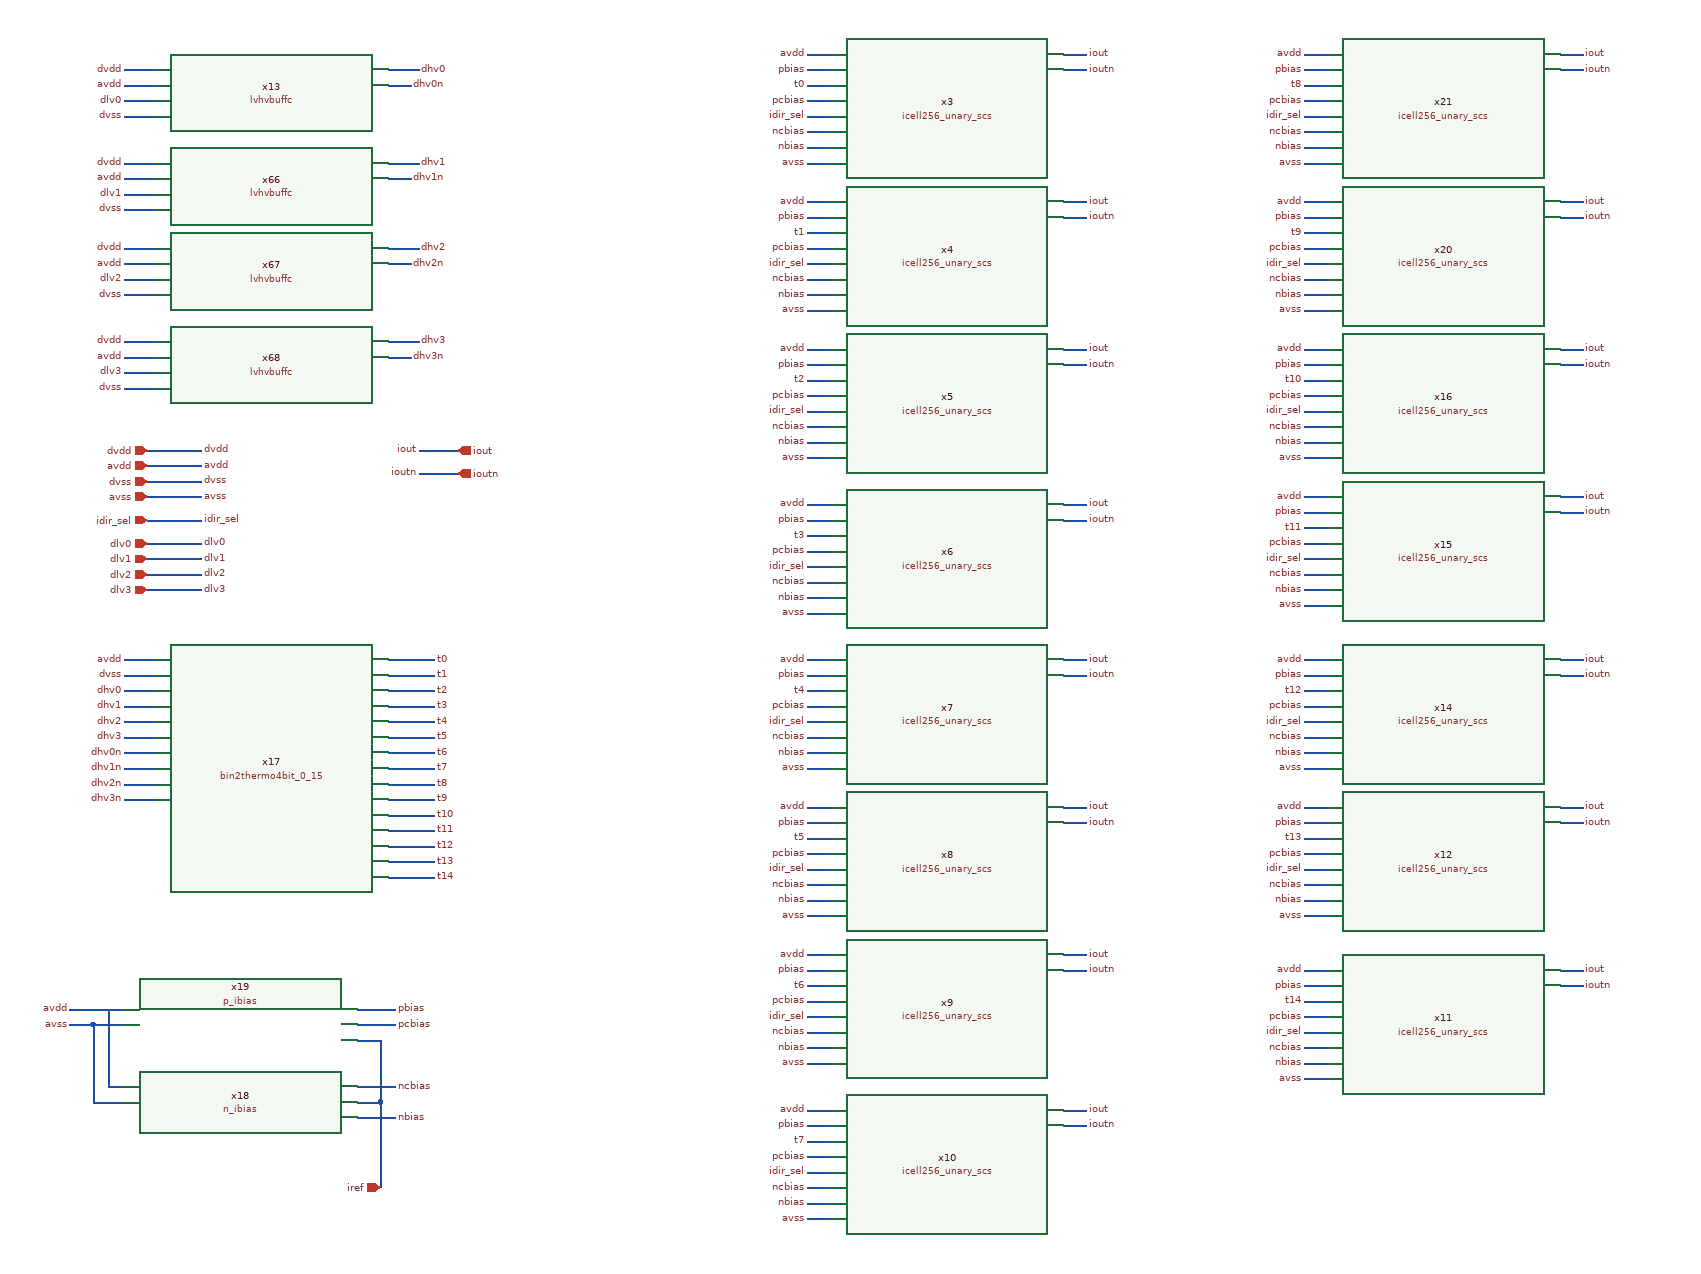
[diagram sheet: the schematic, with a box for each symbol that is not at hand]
v {xschem version=3.4.5 file_version=1.2
}
G {}
K {}
V {}
S {}
E {}
N -50 150 -20 150 {
lab=avss}
N -50 130 -20 130 {
lab=nbias}
N -50 110 -20 110 {
lab=ncbias}
N -50 90 -20 90 {
lab=idir_sel}
N -50 70 -20 70 {
lab=pcbias}
N -50 50 -20 50 {
lab=t0}
N -50 30 -20 30 {
lab=pbias}
N -50 10 -20 10 {
lab=avdd}
N 280 10 310 10 {
lab=iout}
N 280 30 310 30 {
lab=ioutn}
N -50 340 -20 340 {
lab=avss}
N -50 320 -20 320 {
lab=nbias}
N -50 300 -20 300 {
lab=ncbias}
N -50 280 -20 280 {
lab=idir_sel}
N -50 260 -20 260 {
lab=pcbias}
N -50 240 -20 240 {
lab=t1}
N -50 220 -20 220 {
lab=pbias}
N -50 200 -20 200 {
lab=avdd}
N 280 200 310 200 {
lab=iout}
N 280 220 310 220 {
lab=ioutn}
N -50 530 -20 530 {
lab=avss}
N -50 510 -20 510 {
lab=nbias}
N -50 490 -20 490 {
lab=ncbias}
N -50 470 -20 470 {
lab=idir_sel}
N -50 450 -20 450 {
lab=pcbias}
N -50 430 -20 430 {
lab=t2}
N -50 410 -20 410 {
lab=pbias}
N -50 390 -20 390 {
lab=avdd}
N 280 390 310 390 {
lab=iout}
N 280 410 310 410 {
lab=ioutn}
N -50 730 -20 730 {
lab=avss}
N -50 710 -20 710 {
lab=nbias}
N -50 690 -20 690 {
lab=ncbias}
N -50 670 -20 670 {
lab=idir_sel}
N -50 650 -20 650 {
lab=pcbias}
N -50 630 -20 630 {
lab=t3}
N -50 610 -20 610 {
lab=pbias}
N -50 590 -20 590 {
lab=avdd}
N 280 590 310 590 {
lab=iout}
N 280 610 310 610 {
lab=ioutn}
N -50 930 -20 930 {
lab=avss}
N -50 910 -20 910 {
lab=nbias}
N -50 890 -20 890 {
lab=ncbias}
N -50 870 -20 870 {
lab=idir_sel}
N -50 850 -20 850 {
lab=pcbias}
N -50 830 -20 830 {
lab=t4}
N -50 810 -20 810 {
lab=pbias}
N -50 790 -20 790 {
lab=avdd}
N 280 790 310 790 {
lab=iout}
N 280 810 310 810 {
lab=ioutn}
N -50 1120 -20 1120 {
lab=avss}
N -50 1100 -20 1100 {
lab=nbias}
N -50 1080 -20 1080 {
lab=ncbias}
N -50 1060 -20 1060 {
lab=idir_sel}
N -50 1040 -20 1040 {
lab=pcbias}
N -50 1020 -20 1020 {
lab=t5}
N -50 1000 -20 1000 {
lab=pbias}
N -50 980 -20 980 {
lab=avdd}
N 280 980 310 980 {
lab=iout}
N 280 1000 310 1000 {
lab=ioutn}
N -50 1310 -20 1310 {
lab=avss}
N -50 1290 -20 1290 {
lab=nbias}
N -50 1270 -20 1270 {
lab=ncbias}
N -50 1250 -20 1250 {
lab=idir_sel}
N -50 1230 -20 1230 {
lab=pcbias}
N -50 1210 -20 1210 {
lab=t6}
N -50 1190 -20 1190 {
lab=pbias}
N -50 1170 -20 1170 {
lab=avdd}
N 280 1170 310 1170 {
lab=iout}
N 280 1190 310 1190 {
lab=ioutn}
N -50 1510 -20 1510 {
lab=avss}
N -50 1490 -20 1490 {
lab=nbias}
N -50 1470 -20 1470 {
lab=ncbias}
N -50 1450 -20 1450 {
lab=idir_sel}
N -50 1430 -20 1430 {
lab=pcbias}
N -50 1410 -20 1410 {
lab=t7}
N -50 1390 -20 1390 {
lab=pbias}
N -50 1370 -20 1370 {
lab=avdd}
N 280 1370 310 1370 {
lab=iout}
N 280 1390 310 1390 {
lab=ioutn}
N 590 1330 620 1330 {
lab=avss}
N 590 1310 620 1310 {
lab=nbias}
N 590 1290 620 1290 {
lab=ncbias}
N 590 1270 620 1270 {
lab=idir_sel}
N 590 1250 620 1250 {
lab=pcbias}
N 590 1230 620 1230 {
lab=t14}
N 590 1210 620 1210 {
lab=pbias}
N 590 1190 620 1190 {
lab=avdd}
N 920 1190 950 1190 {
lab=iout}
N 920 1210 950 1210 {
lab=ioutn}
N 590 1120 620 1120 {
lab=avss}
N 590 1100 620 1100 {
lab=nbias}
N 590 1080 620 1080 {
lab=ncbias}
N 590 1060 620 1060 {
lab=idir_sel}
N 590 1040 620 1040 {
lab=pcbias}
N 590 1020 620 1020 {
lab=t13}
N 590 1000 620 1000 {
lab=pbias}
N 590 980 620 980 {
lab=avdd}
N 920 980 950 980 {
lab=iout}
N 920 1000 950 1000 {
lab=ioutn}
N 590 930 620 930 {
lab=avss}
N 590 910 620 910 {
lab=nbias}
N 590 890 620 890 {
lab=ncbias}
N 590 870 620 870 {
lab=idir_sel}
N 590 850 620 850 {
lab=pcbias}
N 590 830 620 830 {
lab=t12}
N 590 810 620 810 {
lab=pbias}
N 590 790 620 790 {
lab=avdd}
N 920 790 950 790 {
lab=iout}
N 920 810 950 810 {
lab=ioutn}
N 590 720 620 720 {
lab=avss}
N 590 700 620 700 {
lab=nbias}
N 590 680 620 680 {
lab=ncbias}
N 590 660 620 660 {
lab=idir_sel}
N 590 640 620 640 {
lab=pcbias}
N 590 620 620 620 {
lab=t11}
N 590 600 620 600 {
lab=pbias}
N 590 580 620 580 {
lab=avdd}
N 920 580 950 580 {
lab=iout}
N 920 600 950 600 {
lab=ioutn}
N 590 530 620 530 {
lab=avss}
N 590 510 620 510 {
lab=nbias}
N 590 490 620 490 {
lab=ncbias}
N 590 470 620 470 {
lab=idir_sel}
N 590 450 620 450 {
lab=pcbias}
N 590 430 620 430 {
lab=t10}
N 590 410 620 410 {
lab=pbias}
N 590 390 620 390 {
lab=avdd}
N 920 390 950 390 {
lab=iout}
N 920 410 950 410 {
lab=ioutn}
N 590 340 620 340 {
lab=avss}
N 590 320 620 320 {
lab=nbias}
N 590 300 620 300 {
lab=ncbias}
N 590 280 620 280 {
lab=idir_sel}
N 590 260 620 260 {
lab=pcbias}
N 590 240 620 240 {
lab=t9}
N 590 220 620 220 {
lab=pbias}
N 590 200 620 200 {
lab=avdd}
N 920 200 950 200 {
lab=iout}
N 920 220 950 220 {
lab=ioutn}
N 590 150 620 150 {
lab=avss}
N 590 130 620 130 {
lab=nbias}
N 590 110 620 110 {
lab=ncbias}
N 590 90 620 90 {
lab=idir_sel}
N 590 70 620 70 {
lab=pcbias}
N 590 50 620 50 {
lab=t8}
N 590 30 620 30 {
lab=pbias}
N 590 10 620 10 {
lab=avdd}
N 920 10 950 10 {
lab=iout}
N 920 30 950 30 {
lab=ioutn}
N -930 30 -890 30 {
lab=dvdd}
N -930 50 -890 50 {
lab=avdd}
N -930 70 -890 70 {
lab=dlv0}
N -930 90 -890 90 {
lab=dvss}
N -590 30 -550 30 {
lab=dhv0}
N -930 150 -890 150 {
lab=dvdd}
N -930 170 -890 170 {
lab=avdd}
N -930 190 -890 190 {
lab=dlv1}
N -930 210 -890 210 {
lab=dvss}
N -590 150 -550 150 {
lab=dhv1}
N -930 260 -890 260 {
lab=dvdd}
N -930 280 -890 280 {
lab=avdd}
N -930 300 -890 300 {
lab=dlv2}
N -930 320 -890 320 {
lab=dvss}
N -590 260 -550 260 {
lab=dhv2}
N -930 380 -890 380 {
lab=dvdd}
N -930 400 -890 400 {
lab=avdd}
N -930 420 -890 420 {
lab=dlv3}
N -930 440 -890 440 {
lab=dvss}
N -590 380 -550 380 {
lab=dhv3}
N -590 50 -560 50 {
lab=dhv0n}
N -590 170 -560 170 {
lab=dhv1n}
N -590 280 -560 280 {
lab=dhv2n}
N -590 400 -560 400 {
lab=dhv3n}
N -590 790 -530 790 {
lab=t0}
N -590 810 -530 810 {
lab=t1}
N -590 830 -530 830 {
lab=t2}
N -590 850 -530 850 {
lab=t3}
N -590 870 -530 870 {
lab=t4}
N -590 890 -530 890 {
lab=t5}
N -590 910 -530 910 {
lab=t6}
N -590 930 -530 930 {
lab=t7}
N -590 950 -530 950 {
lab=t8}
N -590 970 -530 970 {
lab=t9}
N -590 990 -530 990 {
lab=t10}
N -590 1010 -530 1010 {
lab=t11}
N -590 1030 -530 1030 {
lab=t12}
N -590 1050 -530 1050 {
lab=t13}
N -590 1070 -530 1070 {
lab=t14}
N -930 790 -890 790 {
lab=avdd}
N -930 810 -890 810 {
lab=dvss}
N -930 830 -890 830 {
lab=dhv0}
N -930 850 -890 850 {
lab=dhv1}
N -930 870 -890 870 {
lab=dhv2}
N -930 890 -890 890 {
lab=dhv3}
N -930 910 -890 910 {
lab=dhv0n}
N -930 930 -890 930 {
lab=dhv1n}
N -930 950 -890 950 {
lab=dhv2n}
N -930 970 -890 970 {
lab=dhv3n}
N -900 520 -830 520 {
lab=dvdd}
N -900 540 -830 540 {
lab=avdd}
N -900 560 -830 560 {
lab=dvss}
N -900 580 -830 580 {
lab=avss}
N -900 640 -830 640 {
lab=dlv0}
N -900 660 -830 660 {
lab=dlv1}
N -900 680 -830 680 {
lab=dlv2}
N -900 700 -830 700 {
lab=dlv3}
N -900 610 -830 610 {
lab=idir_sel}
N -630 1240 -580 1240 {
lab=pbias}
N -630 1260 -580 1260 {
lab=pcbias}
N -600 1280 -600 1360 {
lab=iref}
N -630 1360 -600 1360 {
lab=iref}
N -630 1340 -580 1340 {
lab=ncbias}
N -630 1380 -580 1380 {
lab=nbias}
N -630 1280 -600 1280 {
lab=iref}
N -600 1360 -600 1410 {
lab=iref}
N -600 1410 -600 1470 {
lab=iref}
N -970 1240 -930 1240 {
lab=avdd}
N -970 1260 -930 1260 {
lab=avss}
N -950 1340 -930 1340 {
lab=avdd}
N -950 1240 -950 1340 {
lab=avdd}
N -1000 1240 -970 1240 {
lab=avdd}
N -1000 1260 -970 1260 {
lab=avss}
N -970 1360 -930 1360 {
lab=avss}
N -970 1260 -970 1360 {
lab=avss}
N -550 520 -500 520 {
lab=iout}
N -550 550 -500 550 {
lab=ioutn}
C {devices/lab_pin.sym} -50 10 0 0 {name=p1 sig_type=std_logic lab=avdd}
C {devices/lab_pin.sym} -50 30 0 0 {name=p2 sig_type=std_logic lab=pbias}
C {devices/lab_pin.sym} -50 50 0 0 {name=p3 sig_type=std_logic lab=t0}
C {devices/lab_pin.sym} -50 70 0 0 {name=p4 sig_type=std_logic lab=pcbias}
C {devices/lab_pin.sym} -50 90 0 0 {name=p5 sig_type=std_logic lab=idir_sel}
C {devices/lab_pin.sym} -50 110 0 0 {name=p6 sig_type=std_logic lab=ncbias}
C {devices/lab_pin.sym} -50 130 0 0 {name=p7 sig_type=std_logic lab=nbias}
C {devices/lab_pin.sym} -50 150 0 0 {name=p8 sig_type=std_logic lab=avss}
C {devices/lab_pin.sym} 310 10 0 1 {name=p9 sig_type=std_logic lab=iout}
C {devices/lab_pin.sym} 310 30 0 1 {name=p10 sig_type=std_logic lab=ioutn}
C {devices/lab_pin.sym} -50 200 0 0 {name=p11 sig_type=std_logic lab=avdd}
C {devices/lab_pin.sym} -50 220 0 0 {name=p12 sig_type=std_logic lab=pbias}
C {devices/lab_pin.sym} -50 240 0 0 {name=p13 sig_type=std_logic lab=t1}
C {devices/lab_pin.sym} -50 260 0 0 {name=p14 sig_type=std_logic lab=pcbias}
C {devices/lab_pin.sym} -50 280 0 0 {name=p15 sig_type=std_logic lab=idir_sel}
C {devices/lab_pin.sym} -50 300 0 0 {name=p16 sig_type=std_logic lab=ncbias}
C {devices/lab_pin.sym} -50 320 0 0 {name=p17 sig_type=std_logic lab=nbias}
C {devices/lab_pin.sym} -50 340 0 0 {name=p18 sig_type=std_logic lab=avss}
C {devices/lab_pin.sym} 310 200 0 1 {name=p19 sig_type=std_logic lab=iout}
C {devices/lab_pin.sym} 310 220 0 1 {name=p20 sig_type=std_logic lab=ioutn}
C {devices/lab_pin.sym} -50 390 0 0 {name=p21 sig_type=std_logic lab=avdd}
C {devices/lab_pin.sym} -50 410 0 0 {name=p22 sig_type=std_logic lab=pbias}
C {devices/lab_pin.sym} -50 450 0 0 {name=p24 sig_type=std_logic lab=pcbias}
C {devices/lab_pin.sym} -50 470 0 0 {name=p25 sig_type=std_logic lab=idir_sel}
C {devices/lab_pin.sym} -50 490 0 0 {name=p26 sig_type=std_logic lab=ncbias}
C {devices/lab_pin.sym} -50 510 0 0 {name=p27 sig_type=std_logic lab=nbias}
C {devices/lab_pin.sym} -50 530 0 0 {name=p28 sig_type=std_logic lab=avss}
C {devices/lab_pin.sym} 310 390 0 1 {name=p29 sig_type=std_logic lab=iout}
C {devices/lab_pin.sym} 310 410 0 1 {name=p30 sig_type=std_logic lab=ioutn}
C {devices/lab_pin.sym} -50 590 0 0 {name=p31 sig_type=std_logic lab=avdd}
C {devices/lab_pin.sym} -50 610 0 0 {name=p32 sig_type=std_logic lab=pbias}
C {devices/lab_pin.sym} -50 630 0 0 {name=p33 sig_type=std_logic lab=t3}
C {devices/lab_pin.sym} -50 650 0 0 {name=p34 sig_type=std_logic lab=pcbias}
C {devices/lab_pin.sym} -50 670 0 0 {name=p35 sig_type=std_logic lab=idir_sel}
C {devices/lab_pin.sym} -50 690 0 0 {name=p36 sig_type=std_logic lab=ncbias}
C {devices/lab_pin.sym} -50 710 0 0 {name=p37 sig_type=std_logic lab=nbias}
C {devices/lab_pin.sym} -50 730 0 0 {name=p38 sig_type=std_logic lab=avss}
C {devices/lab_pin.sym} 310 590 0 1 {name=p39 sig_type=std_logic lab=iout}
C {devices/lab_pin.sym} 310 610 0 1 {name=p40 sig_type=std_logic lab=ioutn}
C {devices/lab_pin.sym} -50 790 0 0 {name=p41 sig_type=std_logic lab=avdd}
C {devices/lab_pin.sym} -50 810 0 0 {name=p42 sig_type=std_logic lab=pbias}
C {devices/lab_pin.sym} -50 850 0 0 {name=p44 sig_type=std_logic lab=pcbias}
C {devices/lab_pin.sym} -50 870 0 0 {name=p45 sig_type=std_logic lab=idir_sel}
C {devices/lab_pin.sym} -50 890 0 0 {name=p46 sig_type=std_logic lab=ncbias}
C {devices/lab_pin.sym} -50 910 0 0 {name=p47 sig_type=std_logic lab=nbias}
C {devices/lab_pin.sym} -50 930 0 0 {name=p48 sig_type=std_logic lab=avss}
C {devices/lab_pin.sym} 310 790 0 1 {name=p49 sig_type=std_logic lab=iout}
C {devices/lab_pin.sym} 310 810 0 1 {name=p50 sig_type=std_logic lab=ioutn}
C {devices/lab_pin.sym} -50 980 0 0 {name=p51 sig_type=std_logic lab=avdd}
C {devices/lab_pin.sym} -50 1000 0 0 {name=p52 sig_type=std_logic lab=pbias}
C {devices/lab_pin.sym} -50 1040 0 0 {name=p54 sig_type=std_logic lab=pcbias}
C {devices/lab_pin.sym} -50 1060 0 0 {name=p55 sig_type=std_logic lab=idir_sel}
C {devices/lab_pin.sym} -50 1080 0 0 {name=p56 sig_type=std_logic lab=ncbias}
C {devices/lab_pin.sym} -50 1100 0 0 {name=p57 sig_type=std_logic lab=nbias}
C {devices/lab_pin.sym} -50 1120 0 0 {name=p58 sig_type=std_logic lab=avss}
C {devices/lab_pin.sym} 310 980 0 1 {name=p59 sig_type=std_logic lab=iout}
C {devices/lab_pin.sym} 310 1000 0 1 {name=p60 sig_type=std_logic lab=ioutn}
C {devices/lab_pin.sym} -50 1170 0 0 {name=p61 sig_type=std_logic lab=avdd}
C {devices/lab_pin.sym} -50 1190 0 0 {name=p62 sig_type=std_logic lab=pbias}
C {devices/lab_pin.sym} -50 1230 0 0 {name=p64 sig_type=std_logic lab=pcbias}
C {devices/lab_pin.sym} -50 1250 0 0 {name=p65 sig_type=std_logic lab=idir_sel}
C {devices/lab_pin.sym} -50 1270 0 0 {name=p66 sig_type=std_logic lab=ncbias}
C {devices/lab_pin.sym} -50 1290 0 0 {name=p67 sig_type=std_logic lab=nbias}
C {devices/lab_pin.sym} -50 1310 0 0 {name=p68 sig_type=std_logic lab=avss}
C {devices/lab_pin.sym} 310 1170 0 1 {name=p69 sig_type=std_logic lab=iout}
C {devices/lab_pin.sym} 310 1190 0 1 {name=p70 sig_type=std_logic lab=ioutn}
C {devices/lab_pin.sym} -50 1370 0 0 {name=p71 sig_type=std_logic lab=avdd}
C {devices/lab_pin.sym} -50 1390 0 0 {name=p72 sig_type=std_logic lab=pbias}
C {devices/lab_pin.sym} -50 1410 0 0 {name=p73 sig_type=std_logic lab=t7}
C {devices/lab_pin.sym} -50 1430 0 0 {name=p74 sig_type=std_logic lab=pcbias}
C {devices/lab_pin.sym} -50 1450 0 0 {name=p75 sig_type=std_logic lab=idir_sel}
C {devices/lab_pin.sym} -50 1470 0 0 {name=p76 sig_type=std_logic lab=ncbias}
C {devices/lab_pin.sym} -50 1490 0 0 {name=p77 sig_type=std_logic lab=nbias}
C {devices/lab_pin.sym} -50 1510 0 0 {name=p78 sig_type=std_logic lab=avss}
C {devices/lab_pin.sym} 310 1370 0 1 {name=p79 sig_type=std_logic lab=iout}
C {devices/lab_pin.sym} 310 1390 0 1 {name=p80 sig_type=std_logic lab=ioutn}
C {devices/lab_pin.sym} -50 430 0 0 {name=p23 sig_type=std_logic lab=t2}
C {devices/lab_pin.sym} -50 830 0 0 {name=p43 sig_type=std_logic lab=t4}
C {devices/lab_pin.sym} -50 1020 0 0 {name=p53 sig_type=std_logic lab=t5}
C {devices/lab_pin.sym} -50 1210 0 0 {name=p63 sig_type=std_logic lab=t6}
C {devices/lab_pin.sym} 590 1190 0 0 {name=p81 sig_type=std_logic lab=avdd}
C {devices/lab_pin.sym} 590 1210 0 0 {name=p82 sig_type=std_logic lab=pbias}
C {devices/lab_pin.sym} 590 1230 0 0 {name=p83 sig_type=std_logic lab=t14}
C {devices/lab_pin.sym} 590 1250 0 0 {name=p84 sig_type=std_logic lab=pcbias}
C {devices/lab_pin.sym} 590 1270 0 0 {name=p85 sig_type=std_logic lab=idir_sel}
C {devices/lab_pin.sym} 590 1290 0 0 {name=p86 sig_type=std_logic lab=ncbias}
C {devices/lab_pin.sym} 590 1310 0 0 {name=p87 sig_type=std_logic lab=nbias}
C {devices/lab_pin.sym} 590 1330 0 0 {name=p88 sig_type=std_logic lab=avss}
C {devices/lab_pin.sym} 950 1190 0 1 {name=p89 sig_type=std_logic lab=iout}
C {devices/lab_pin.sym} 950 1210 0 1 {name=p90 sig_type=std_logic lab=ioutn}
C {devices/lab_pin.sym} 590 980 0 0 {name=p91 sig_type=std_logic lab=avdd}
C {devices/lab_pin.sym} 590 1000 0 0 {name=p92 sig_type=std_logic lab=pbias}
C {devices/lab_pin.sym} 590 1020 0 0 {name=p93 sig_type=std_logic lab=t13}
C {devices/lab_pin.sym} 590 1040 0 0 {name=p94 sig_type=std_logic lab=pcbias}
C {devices/lab_pin.sym} 590 1060 0 0 {name=p95 sig_type=std_logic lab=idir_sel}
C {devices/lab_pin.sym} 590 1080 0 0 {name=p96 sig_type=std_logic lab=ncbias}
C {devices/lab_pin.sym} 590 1100 0 0 {name=p97 sig_type=std_logic lab=nbias}
C {devices/lab_pin.sym} 590 1120 0 0 {name=p98 sig_type=std_logic lab=avss}
C {devices/lab_pin.sym} 950 980 0 1 {name=p99 sig_type=std_logic lab=iout}
C {devices/lab_pin.sym} 950 1000 0 1 {name=p100 sig_type=std_logic lab=ioutn}
C {devices/lab_pin.sym} 590 790 0 0 {name=p101 sig_type=std_logic lab=avdd}
C {devices/lab_pin.sym} 590 810 0 0 {name=p102 sig_type=std_logic lab=pbias}
C {devices/lab_pin.sym} 590 830 0 0 {name=p103 sig_type=std_logic lab=t12}
C {devices/lab_pin.sym} 590 850 0 0 {name=p104 sig_type=std_logic lab=pcbias}
C {devices/lab_pin.sym} 590 870 0 0 {name=p105 sig_type=std_logic lab=idir_sel}
C {devices/lab_pin.sym} 590 890 0 0 {name=p106 sig_type=std_logic lab=ncbias}
C {devices/lab_pin.sym} 590 910 0 0 {name=p107 sig_type=std_logic lab=nbias}
C {devices/lab_pin.sym} 590 930 0 0 {name=p108 sig_type=std_logic lab=avss}
C {devices/lab_pin.sym} 950 790 0 1 {name=p109 sig_type=std_logic lab=iout}
C {devices/lab_pin.sym} 950 810 0 1 {name=p110 sig_type=std_logic lab=ioutn}
C {devices/lab_pin.sym} 590 580 0 0 {name=p111 sig_type=std_logic lab=avdd}
C {devices/lab_pin.sym} 590 600 0 0 {name=p112 sig_type=std_logic lab=pbias}
C {devices/lab_pin.sym} 590 620 0 0 {name=p113 sig_type=std_logic lab=t11}
C {devices/lab_pin.sym} 590 640 0 0 {name=p114 sig_type=std_logic lab=pcbias}
C {devices/lab_pin.sym} 590 660 0 0 {name=p115 sig_type=std_logic lab=idir_sel}
C {devices/lab_pin.sym} 590 680 0 0 {name=p116 sig_type=std_logic lab=ncbias}
C {devices/lab_pin.sym} 590 700 0 0 {name=p117 sig_type=std_logic lab=nbias}
C {devices/lab_pin.sym} 590 720 0 0 {name=p118 sig_type=std_logic lab=avss}
C {devices/lab_pin.sym} 950 580 0 1 {name=p119 sig_type=std_logic lab=iout}
C {devices/lab_pin.sym} 950 600 0 1 {name=p120 sig_type=std_logic lab=ioutn}
C {devices/lab_pin.sym} 590 390 0 0 {name=p131 sig_type=std_logic lab=avdd}
C {devices/lab_pin.sym} 590 410 0 0 {name=p132 sig_type=std_logic lab=pbias}
C {devices/lab_pin.sym} 590 430 0 0 {name=p133 sig_type=std_logic lab=t10}
C {devices/lab_pin.sym} 590 450 0 0 {name=p134 sig_type=std_logic lab=pcbias}
C {devices/lab_pin.sym} 590 470 0 0 {name=p135 sig_type=std_logic lab=idir_sel}
C {devices/lab_pin.sym} 590 490 0 0 {name=p136 sig_type=std_logic lab=ncbias}
C {devices/lab_pin.sym} 590 510 0 0 {name=p137 sig_type=std_logic lab=nbias}
C {devices/lab_pin.sym} 590 530 0 0 {name=p138 sig_type=std_logic lab=avss}
C {devices/lab_pin.sym} 950 390 0 1 {name=p139 sig_type=std_logic lab=iout}
C {devices/lab_pin.sym} 950 410 0 1 {name=p140 sig_type=std_logic lab=ioutn}
C {devices/lab_pin.sym} 590 200 0 0 {name=p141 sig_type=std_logic lab=avdd}
C {devices/lab_pin.sym} 590 220 0 0 {name=p142 sig_type=std_logic lab=pbias}
C {devices/lab_pin.sym} 590 240 0 0 {name=p143 sig_type=std_logic lab=t9}
C {devices/lab_pin.sym} 590 260 0 0 {name=p144 sig_type=std_logic lab=pcbias}
C {devices/lab_pin.sym} 590 280 0 0 {name=p145 sig_type=std_logic lab=idir_sel}
C {devices/lab_pin.sym} 590 300 0 0 {name=p146 sig_type=std_logic lab=ncbias}
C {devices/lab_pin.sym} 590 320 0 0 {name=p147 sig_type=std_logic lab=nbias}
C {devices/lab_pin.sym} 590 340 0 0 {name=p148 sig_type=std_logic lab=avss}
C {devices/lab_pin.sym} 950 200 0 1 {name=p149 sig_type=std_logic lab=iout}
C {devices/lab_pin.sym} 950 220 0 1 {name=p150 sig_type=std_logic lab=ioutn}
C {devices/lab_pin.sym} 590 10 0 0 {name=p641 sig_type=std_logic lab=avdd}
C {devices/lab_pin.sym} 590 30 0 0 {name=p642 sig_type=std_logic lab=pbias}
C {devices/lab_pin.sym} 590 50 0 0 {name=p643 sig_type=std_logic lab=t8}
C {devices/lab_pin.sym} 590 70 0 0 {name=p644 sig_type=std_logic lab=pcbias}
C {devices/lab_pin.sym} 590 90 0 0 {name=p645 sig_type=std_logic lab=idir_sel}
C {devices/lab_pin.sym} 590 110 0 0 {name=p646 sig_type=std_logic lab=ncbias}
C {devices/lab_pin.sym} 590 130 0 0 {name=p647 sig_type=std_logic lab=nbias}
C {devices/lab_pin.sym} 590 150 0 0 {name=p648 sig_type=std_logic lab=avss}
C {devices/lab_pin.sym} 950 10 0 1 {name=p649 sig_type=std_logic lab=iout}
C {devices/lab_pin.sym} 950 30 0 1 {name=p650 sig_type=std_logic lab=ioutn}
C {devices/lab_pin.sym} -930 30 0 0 {name=p121 sig_type=std_logic lab=dvdd}
C {devices/lab_pin.sym} -930 50 0 0 {name=p122 sig_type=std_logic lab=avdd}
C {devices/lab_pin.sym} -930 70 0 0 {name=p123 sig_type=std_logic lab=dlv0}
C {devices/lab_pin.sym} -930 90 0 0 {name=p124 sig_type=std_logic lab=dvss}
C {devices/lab_pin.sym} -550 30 0 1 {name=p125 sig_type=std_logic lab=dhv0}
C {devices/lab_pin.sym} -930 150 0 0 {name=p126 sig_type=std_logic lab=dvdd}
C {devices/lab_pin.sym} -930 170 0 0 {name=p127 sig_type=std_logic lab=avdd}
C {devices/lab_pin.sym} -930 190 0 0 {name=p128 sig_type=std_logic lab=dlv1}
C {devices/lab_pin.sym} -930 210 0 0 {name=p129 sig_type=std_logic lab=dvss}
C {devices/lab_pin.sym} -550 150 0 1 {name=p130 sig_type=std_logic lab=dhv1}
C {devices/lab_pin.sym} -930 260 0 0 {name=p651 sig_type=std_logic lab=dvdd}
C {devices/lab_pin.sym} -930 280 0 0 {name=p652 sig_type=std_logic lab=avdd}
C {devices/lab_pin.sym} -930 300 0 0 {name=p653 sig_type=std_logic lab=dlv2}
C {devices/lab_pin.sym} -930 320 0 0 {name=p654 sig_type=std_logic lab=dvss}
C {devices/lab_pin.sym} -550 260 0 1 {name=p655 sig_type=std_logic lab=dhv2}
C {devices/lab_pin.sym} -930 380 0 0 {name=p656 sig_type=std_logic lab=dvdd}
C {devices/lab_pin.sym} -930 400 0 0 {name=p657 sig_type=std_logic lab=avdd}
C {devices/lab_pin.sym} -930 420 0 0 {name=p658 sig_type=std_logic lab=dlv3}
C {devices/lab_pin.sym} -930 440 0 0 {name=p659 sig_type=std_logic lab=dvss}
C {devices/lab_pin.sym} -550 380 0 1 {name=p660 sig_type=std_logic lab=dhv3}
C {lvhvbuffc.sym} -740 60 0 0 {name=x13}
C {lvhvbuffc.sym} -740 180 0 0 {name=x66}
C {lvhvbuffc.sym} -740 290 0 0 {name=x67}
C {lvhvbuffc.sym} -740 410 0 0 {name=x68}
C {devices/lab_pin.sym} -560 50 0 1 {name=p671 sig_type=std_logic lab=dhv0n}
C {devices/lab_pin.sym} -560 170 0 1 {name=p672 sig_type=std_logic lab=dhv1n}
C {devices/lab_pin.sym} -560 280 0 1 {name=p673 sig_type=std_logic lab=dhv2n}
C {devices/lab_pin.sym} -560 400 0 1 {name=p674 sig_type=std_logic lab=dhv3n}
C {bin2thermo4bit_0_15.sym} -740 930 0 0 {name=x17}
C {devices/lab_pin.sym} -530 790 0 1 {name=p161 sig_type=std_logic lab=t0}
C {devices/lab_pin.sym} -530 810 0 1 {name=p162 sig_type=std_logic lab=t1}
C {devices/lab_pin.sym} -530 830 0 1 {name=p163 sig_type=std_logic lab=t2}
C {devices/lab_pin.sym} -530 850 0 1 {name=p164 sig_type=std_logic lab=t3}
C {devices/lab_pin.sym} -530 870 0 1 {name=p165 sig_type=std_logic lab=t4}
C {devices/lab_pin.sym} -530 890 0 1 {name=p166 sig_type=std_logic lab=t5}
C {devices/lab_pin.sym} -530 910 0 1 {name=p167 sig_type=std_logic lab=t6}
C {devices/lab_pin.sym} -530 930 0 1 {name=p168 sig_type=std_logic lab=t7}
C {devices/lab_pin.sym} -530 950 0 1 {name=p169 sig_type=std_logic lab=t8}
C {devices/lab_pin.sym} -530 970 0 1 {name=p170 sig_type=std_logic lab=t9}
C {devices/lab_pin.sym} -530 990 0 1 {name=p171 sig_type=std_logic lab=t10}
C {devices/lab_pin.sym} -530 1010 0 1 {name=p172 sig_type=std_logic lab=t11}
C {devices/lab_pin.sym} -530 1030 0 1 {name=p173 sig_type=std_logic lab=t12}
C {devices/lab_pin.sym} -530 1050 0 1 {name=p174 sig_type=std_logic lab=t13}
C {devices/lab_pin.sym} -530 1070 0 1 {name=p175 sig_type=std_logic lab=t14}
C {devices/lab_pin.sym} -930 790 0 0 {name=p177 sig_type=std_logic lab=avdd}
C {devices/lab_pin.sym} -930 810 0 0 {name=p178 sig_type=std_logic lab=dvss}
C {devices/lab_pin.sym} -930 830 0 0 {name=p179 sig_type=std_logic lab=dhv0}
C {devices/lab_pin.sym} -930 850 0 0 {name=p180 sig_type=std_logic lab=dhv1}
C {devices/lab_pin.sym} -930 870 0 0 {name=p181 sig_type=std_logic lab=dhv2}
C {devices/lab_pin.sym} -930 890 0 0 {name=p182 sig_type=std_logic lab=dhv3}
C {devices/lab_pin.sym} -930 910 0 0 {name=p183 sig_type=std_logic lab=dhv0n}
C {devices/lab_pin.sym} -930 930 0 0 {name=p184 sig_type=std_logic lab=dhv1n}
C {devices/lab_pin.sym} -930 950 0 0 {name=p185 sig_type=std_logic lab=dhv2n}
C {devices/lab_pin.sym} -930 970 0 0 {name=p186 sig_type=std_logic lab=dhv3n}
C {devices/ipin.sym} -900 520 0 0 {name=p187 lab=dvdd}
C {devices/ipin.sym} -900 540 0 0 {name=p188 lab=avdd}
C {devices/ipin.sym} -900 560 0 0 {name=p189 lab=dvss}
C {devices/ipin.sym} -900 580 0 0 {name=p190 lab=avss}
C {devices/lab_pin.sym} -830 520 0 1 {name=p191 sig_type=std_logic lab=dvdd}
C {devices/lab_pin.sym} -830 540 0 1 {name=p192 sig_type=std_logic lab=avdd}
C {devices/lab_pin.sym} -830 560 0 1 {name=p193 sig_type=std_logic lab=dvss}
C {devices/lab_pin.sym} -830 580 0 1 {name=p194 sig_type=std_logic lab=avss}
C {devices/ipin.sym} -900 640 0 0 {name=p195 lab=dlv0}
C {devices/ipin.sym} -900 660 0 0 {name=p196 lab=dlv1}
C {devices/ipin.sym} -900 680 0 0 {name=p197 lab=dlv2}
C {devices/ipin.sym} -900 700 0 0 {name=p198 lab=dlv3}
C {devices/lab_pin.sym} -830 700 0 1 {name=p199 sig_type=std_logic lab=dlv3}
C {devices/lab_pin.sym} -830 680 0 1 {name=p200 sig_type=std_logic lab=dlv2}
C {devices/lab_pin.sym} -830 660 0 1 {name=p201 sig_type=std_logic lab=dlv1}
C {devices/lab_pin.sym} -830 640 0 1 {name=p202 sig_type=std_logic lab=dlv0}
C {devices/ipin.sym} -900 610 0 0 {name=p207 lab=idir_sel}
C {devices/lab_pin.sym} -830 610 0 1 {name=p208 sig_type=std_logic lab=idir_sel}
C {n_ibias.sym} -780 1360 0 0 {name=x18}
C {p_ibias.sym} -780 1260 0 0 {name=x19}
C {devices/lab_pin.sym} -580 1240 0 1 {name=p209 sig_type=std_logic lab=pbias}
C {devices/lab_pin.sym} -580 1260 0 1 {name=p210 sig_type=std_logic lab=pcbias}
C {devices/lab_pin.sym} -580 1380 0 1 {name=p211 sig_type=std_logic lab=nbias}
C {devices/lab_pin.sym} -580 1340 0 1 {name=p212 sig_type=std_logic lab=ncbias}
C {devices/iopin.sym} -600 1470 0 0 {name=p213 lab=iref}
C {devices/lab_pin.sym} -1000 1260 0 0 {name=p214 sig_type=std_logic lab=avss}
C {devices/lab_pin.sym} -1000 1240 0 0 {name=p215 sig_type=std_logic lab=avdd}
C {devices/opin.sym} -500 520 0 0 {name=p203 lab=iout}
C {devices/opin.sym} -500 550 0 0 {name=p204 lab=ioutn}
C {devices/lab_pin.sym} -550 520 0 0 {name=p205 sig_type=std_logic lab=iout}
C {devices/lab_pin.sym} -550 550 0 0 {name=p206 sig_type=std_logic lab=ioutn}
C {icell256_unary_scs.sym} 130 80 0 0 {name=x3}
C {icell256_unary_scs.sym} 130 270 0 0 {name=x4}
C {icell256_unary_scs.sym} 130 460 0 0 {name=x5}
C {icell256_unary_scs.sym} 130 660 0 0 {name=x6}
C {icell256_unary_scs.sym} 130 860 0 0 {name=x7}
C {icell256_unary_scs.sym} 130 1050 0 0 {name=x8}
C {icell256_unary_scs.sym} 130 1240 0 0 {name=x9}
C {icell256_unary_scs.sym} 130 1440 0 0 {name=x10}
C {icell256_unary_scs.sym} 770 1260 0 0 {name=x11}
C {icell256_unary_scs.sym} 770 1050 0 0 {name=x12}
C {icell256_unary_scs.sym} 770 860 0 0 {name=x14}
C {icell256_unary_scs.sym} 770 650 0 0 {name=x15}
C {icell256_unary_scs.sym} 770 460 0 0 {name=x16}
C {icell256_unary_scs.sym} 770 270 0 0 {name=x20}
C {icell256_unary_scs.sym} 770 80 0 0 {name=x21}
